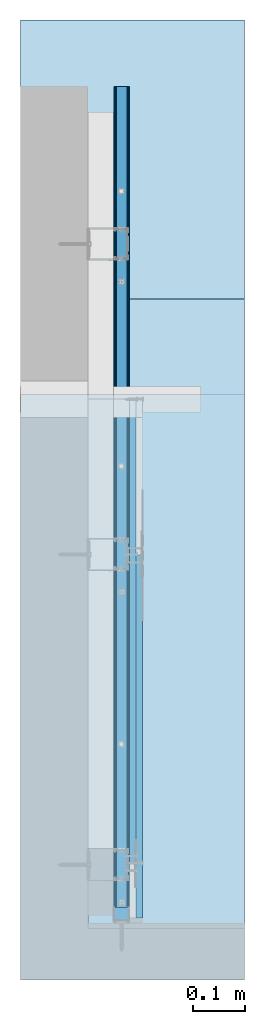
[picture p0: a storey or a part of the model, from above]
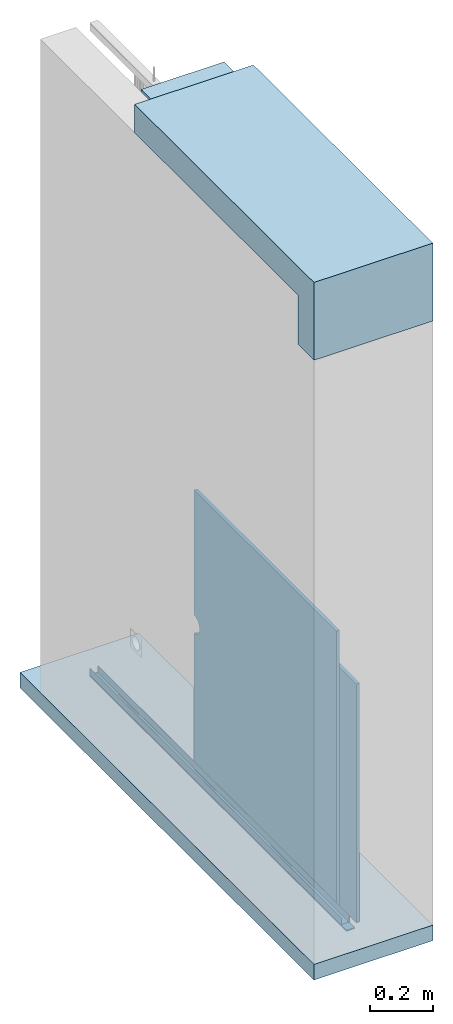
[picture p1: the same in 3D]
Properties of the parts of a building model (IFC2X3)

# File
Description: ViewDefinition [CoordinationView_V2.0]
File name: kolizja nr 5.ifc
Time: 2025-10-29T14:54:42
Written by: IFC-manager for SketchUp (5.5.4)
Made in: SketchUp 2026 (26.0.429)

# IfcSite, Default Site
Description: Description of Default Site; RefElevation: 254 mm

# IfcBuilding, Default Building
Description: Description of Default Building; ElevationOfRefHeight: 0 mm; ElevationOfTerrain: 0 mm

# IfcBuildingStorey, Default Building Storey
In: Default Building
Description: Description of Default Building Storey; Elevation: 57.6156 mm
Parametry kolizji SG - Elementkolizyjnykonstrukcyjnyinstalacyjny: Rura instalacyjna o małej średnicy; ElementsystemuSaintGobain: Okładzina ścienna; Izolacyjnoscakustyczna: niezweryfikowana; Klasaodpornosciogniowej: -; LODlevelofDevelopment: 400; Nrdetalu: 5.57.021; Opis: Detal przejścia rury o małej średnicy przez okładzinę ścienną wykonaną w systemie RIGIPS; Producent: SAINT-GOBAIN; Sposobwykonania: W przypadku koniecznoÅ›ci poprowadzenia przewodu rurowego o maÅ‚ej Å›rednicy ( Ã˜<25mm) przez okÅ‚adzinÄ™ Å›ciennÄ… w systemie RIGIPS naleÅ¼y zaprojektowaÄ‡ jego przebieg w taki sposÃ³b, aby nie kolidowaÅ‚ z profilami pionowymi CD 60. JeÅ¼eli kolizja z profilem CD 60 jest nieunikniona, naleÅ¼y przewidzieÄ‡ i wykonaÄ‡ w Å›cianie dodatkowy profil pionowy CD 60, zapewniajÄ…cy prawidÅ‚owe usztywnienie konstrukcji. W miejscu przejÅ›cia instalacji naleÅ¼y wykonaÄ‡ otwÃ³r okrÄ…gÅ‚y w pÅ‚ytach gipsowo-kartonowych o wymiarach wiÄ™kszych od Å›rednicy rury o 10â€“20 mm. PrzestrzeÅ„ pomiÄ™dzy krawÄ™dziÄ… rury a krawÄ™dziÄ… otworu naleÅ¼y wypeÅ‚niÄ‡ weÅ‚nÄ… mineralnÄ… ISOVER, a nastÄ™pnie na wypeÅ‚nienie zastosowaÄ‡ masÄ™ szpachlowÄ… RIGIPS, zapewniajÄ…c szczelne i estetyczne wykoÅ„czenie powierzchni Å›ciany.; Typkolizji: twarda; Warianty: -

# IfcSlab: Beton#1, Beton
In: Default Building Storey
Type - PredefinedType: FLOOR
Material: Concrete_02_1K
Qto_SlabBaseQuantities - NetVolume: 0.048222 m3; Depth: 59.9996 mm; NetArea: 0.803705 m2

# IfcSlab: Strop#1, Strop
In: Default Building Storey
Type - PredefinedType: FLOOR
Material: Concrete_02_1K
Qto_SlabBaseQuantities - NetVolume: 0.0590179 m3; Depth: 300 mm; NetArea: 0.196726 m2

# IfcSlab: Strop#2, Strop
In: Default Building Storey
Type - PredefinedType: FLOOR
Material: Concrete_04_1K
Qto_SlabBaseQuantities - NetVolume: 0.00426325 m3; Depth: 200 mm; NetArea: 0.0213163 m2

# IfcWall: Kołek rozporowy min. fi 6#10 (7)
In: Default Building Storey
Type - Description: Description of Object
Material: Default

# IfcWall: Kołek rozporowy min. fi 6#11, Kołek rozporowy min. fi 6
In: Default Building Storey
Type - Description: Description of Object
Material: Default

# IfcWall: Kołek rozporowy min. fi 6#12, Kołek rozporowy min. fi 6
In: Default Building Storey
Type - Description: Description of Object
Material: Default

# IfcWall: Kołek rozporowy min. fi 6#13 (9)
In: Default Building Storey
Type - Description: Description of Object
Material: Default

# IfcWall: Kołek rozporowy min. fi 6#14 (9)
In: Default Building Storey
Type - Description: Description of Object
Material: Default

# IfcWall: Kołek rozporowy min. fi 6#7 (4)
In: Default Building Storey
Type - Description: Description of Object
Material: Default

# IfcWall: Kołek rozporowy min. fi 6#8 (7)
In: Default Building Storey
Type - Description: Description of Object
Material: Default

# IfcWall: Kołek rozporowy min. fi 6#9 (4)
In: Default Building Storey
Type - Description: Description of Object
Material: Default

# IfcWall: Masa szpachlowa konstrukcyjna RIGIPS
In: Default Building Storey
Type - Description: Description of Object
Material: Undefined5
Qto_WallBaseQuantities - NetVolume: 0.0000660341 m3; Width: 3.20005 mm; Length: 91 mm; NetSideArea: 0.0206353 m2

# IfcWall: Masa szpachlowa konstrukcyjna RIGIPS#1, Masa szpachlowa konstrukcyjna RIGIPS
In: Default Building Storey
Type - Description: Description of Object
Material: Undefined5
Qto_WallBaseQuantities - NetVolume: 0.000250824 m3

# IfcWall: Masa szpachlowa konstrukcyjna RIGIPS#4, Masa szpachlowa konstrukcyjna RIGIPS
In: Default Building Storey
Type - Description: Description of Object
Material: Undefined5
Qto_WallBaseQuantities - NetVolume: 0.00011014 m3; Width: 3.20005 mm; Length: 91 mm; NetSideArea: 0.0344181 m2

# IfcWall: Masa szpachlowa konstrukcyjna RIGIPS#5, Masa szpachlowa konstrukcyjna RIGIPS
In: Default Building Storey
Type - Description: Description of Object
Material: Undefined5
Qto_WallBaseQuantities - NetVolume: 0.000628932 m3

# IfcWall: Masa szpachlowa wykończeniowa RIGIPS
In: Default Building Storey
Type - Description: Description of Object
Material: Undefined2
Qto_WallBaseQuantities - NetVolume: 0.0000477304 m3; Width: 0.959873 mm; Length: 250 mm; NetSideArea: 0.0497257 m2

# IfcWall: Profil RIGIPS CD 60 GypSerra®/Ultrastil®#3 (3)
In: Default Building Storey
Type - Description: Description of Object
Material: Default

# IfcWall: Profil RIGIPS UD 30 GypSerra®/Ultrastil®
In: Default Building Storey
Type - Description: Description of Object
Material: Undefined9
Qto_WallBaseQuantities - NetVolume: 0.0000727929 m3

# IfcWall: Profil RIGIPS UD 30 GypSerra®/Ultrastil®#1, Profil RIGIPS UD 30 GypSerra®/Ultrastil®
In: Default Building Storey
Type - Description: Description of Object
Material: Undefined9
Qto_WallBaseQuantities - NetVolume: 0.0000742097 m3

# IfcWall: Profil RIGIPS UD 30 GypSerra®/Ultrastil®#2, Profil RIGIPS UD 30 GypSerra®/Ultrastil®
In: Default Building Storey
Type - Description: Description of Object
Material: Undefined9
Qto_WallBaseQuantities - NetVolume: 0.000113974 m3

# IfcWall: Przewód instalacyjny - okrągły
In: Default Building Storey
Material: M00_Soft_Cloud
Qto_WallBaseQuantities - NetVolume: 0.0000799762 m3

# IfcWall: Płyta gipsowo-kartonowa RIGIPS PRO (4PRO™)#2, Płyta gipsowo-kartonowa RIGIPS PRO (4PRO™)
In: Default Building Storey
Type - Description: Description of Object
Material: Undefined7
Qto_WallBaseQuantities - NetVolume: 0.00134186 m3; Width: 12.5 mm; Length: 104.369 mm; NetSideArea: 0.107349 m2

# IfcWall: Płyta gipsowo-kartonowa RIGIPS PRO (4PRO™)#4, Płyta gipsowo-kartonowa RIGIPS PRO (4PRO™)
In: Default Building Storey
Type - Description: Description of Object
Material: Undefined7
Qto_WallBaseQuantities - NetVolume: 0.00800702 m3; Width: 12.5 mm; Length: 700.477 mm; NetSideArea: 0.640562 m2

# IfcWall: Płyta gipsowo-kartonowa RIGIPS PRO (4PRO™)#5, Płyta gipsowo-kartonowa RIGIPS PRO (4PRO™)
In: Default Building Storey
Type - Description: Description of Object
Material: Undefined7
Qto_WallBaseQuantities - NetVolume: 0.0118819 m3; Width: 12.5 mm; Length: 898.639 mm; NetSideArea: 0.950551 m2

# IfcWall: Płyta gipsowo-kartonowa RIGIPS PRO (4PRO™)#6, Płyta gipsowo-kartonowa RIGIPS PRO (4PRO™)
In: Default Building Storey
Type - Description: Description of Object
Material: Undefined7
Qto_WallBaseQuantities - NetVolume: 0.00340008 m3; Width: 12.5 mm; Length: 301.531 mm; NetSideArea: 0.272006 m2

# IfcWall: Taśma spoinowa RIGIPS#1, Taśma spoinowa RIGIPS
In: Default Building Storey
Type - Description: Description of Object
Material: Undefined8
Qto_WallBaseQuantities - NetVolume: 0.0000226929 m3; Width: 0.500202 mm; Length: 50 mm; NetSideArea: 0.0453675 m2

# IfcWall: Taśma uszczelniająca piankowa RIGIPS szer.30mm#1 (9)
In: Default Building Storey
Type - Description: Description of Object
Material: Default

# IfcWall: Taśma uszczelniająca piankowa RIGIPS#3 (2)
In: Default Building Storey
Type - Description: Description of Object
Material: Undefined13
Qto_WallBaseQuantities - NetVolume: 0.000145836 m3

# IfcWall: Taśma uszczelniająca piankowa RIGIPS#4, Taśma uszczelniająca piankowa RIGIPS
In: Default Building Storey
Type - Description: Description of Object
Material: Undefined13
Qto_WallBaseQuantities - NetVolume: 0.00022365 m3

# IfcWall: Uchwyt Rigips ES do profili CD60 (9)
In: Default Building Storey
Type - Description: Description of Object
Name | Material
3 x Uchwyt Rigips ES do profili CD60 | Default
6 x Uchwyt Rigips ES do profili CD60 | Undefined3

# IfcWall: Uszczelnienie wełną mineralną ISOVER#1, Uszczelnienie wełną mineralną ISOVER
In: Default Building Storey
Material: D02_Buttercup_Glow

# IfcWall: Wkręt RIGIPS "pchełka" 3,9x11mm#1 (9)
In: Default Building Storey
Type - Description: Description of Object
Name | Material
3 x Wkręt RIGIPS "pchełka" 3,9x11mm | Default
6 x Wkręt RIGIPS "pchełka" 3,9x11mm | Undefined4

# IfcWall: Wkręt RIGIPS "pchełka" 3,9x11mm#2 (9)
In: Default Building Storey
Type - Description: Description of Object
Name | Material
3 x Wkręt RIGIPS "pchełka" 3,9x11mm | Default
6 x Wkręt RIGIPS "pchełka" 3,9x11mm | Undefined4

# IfcWall: Wkręt RIGIPS "pchełka" 3,9x11mm#3 (9)
In: Default Building Storey
Type - Description: Description of Object
Name | Material
3 x Wkręt RIGIPS "pchełka" 3,9x11mm | Default
6 x Wkręt RIGIPS "pchełka" 3,9x11mm | Undefined4

# IfcWall: Wkręt RIGIPS "pchełka" 3,9x11mm#4 (9)
In: Default Building Storey
Type - Description: Description of Object
Material: Undefined4

# IfcWall: Wkręt RIGIPS TN 25#11 (4)
In: Default Building Storey
Type - Description: Description of Object
Material: Default

# IfcWall: Wkręt RIGIPS TN 25#7 (2)
In: Default Building Storey
Type - Description: Description of Object
Material: Undefined6

# IfcWall: Wkręt RIGIPS TN 25#8 (2)
In: Default Building Storey
Type - Description: Description of Object
Material: Undefined6

# IfcWall: Wkręt RIGIPS TN 35#10 (2)
In: Default Building Storey
Type - Description: Description of Object
Material: Undefined6

# IfcWall: Wkręt RIGIPS TN 35#11 (2)
In: Default Building Storey
Type - Description: Description of Object
Material: Undefined6

# IfcWall: Wkręt RIGIPS TN 35#13, Wkręt RIGIPS TN 35
In: Default Building Storey
Type - Description: Description of Object
Material: Undefined6

# IfcWall: Wkręt RIGIPS TN 35#14, Wkręt RIGIPS TN 35
In: Default Building Storey
Type - Description: Description of Object
Material: Undefined6

# IfcWall: Wkręt RIGIPS TN 35#15 (2)
In: Default Building Storey
Type - Description: Description of Object
Material: Undefined6

# IfcWall: Wkręt RIGIPS TN 35#16, Wkręt RIGIPS TN 35
In: Default Building Storey
Type - Description: Description of Object
Material: Undefined6

# IfcWall: Wkręt RIGIPS TN 35#17, Wkręt RIGIPS TN 35
In: Default Building Storey
Type - Description: Description of Object
Material: Undefined6

# IfcWall: Wkręt RIGIPS TN 35#18 (2)
In: Default Building Storey
Type - Description: Description of Object
Material: Undefined6

# IfcWall: Wkręt RIGIPS TN 35#19, Wkręt RIGIPS TN 35
In: Default Building Storey
Type - Description: Description of Object
Material: Undefined6

# IfcWall: Wkręt RIGIPS TN 35#20, Wkręt RIGIPS TN 35
In: Default Building Storey
Type - Description: Description of Object
Material: Undefined6

# IfcWall: Wkręt RIGIPS TN 35#21 (2)
In: Default Building Storey
Type - Description: Description of Object
Material: Undefined6

# IfcWall: Wypełnienie masą szpachlową RIGIPS (2)
In: Default Building Storey
Material: M08_Obsidian_Black
Qto_WallBaseQuantities - NetVolume: 0.0000119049 m3; Width: 12.5 mm; Length: 35 mm; NetSideArea: 0.000952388 m2

# IfcWall: Wypełnienie z wełny mineralnej szklanej ISOVER#1, Wypełnienie z wełny mineralnej szklanej ISOVER
In: Default Building Storey
Type - Description: Description of Object
Material: Undefined
Qto_WallBaseQuantities - NetVolume: 0.00451831 m3; Width: 50 mm; Length: 224.108 mm; NetSideArea: 0.0903662 m2

# IfcWall: Wypełnienie z wełny mineralnej szklanej ISOVER#12 (2)
In: Default Building Storey
Type - Description: Description of Object
Material: Default

# IfcWall: Wypełnienie z wełny mineralnej szklanej ISOVER#13, Wypełnienie z wełny mineralnej szklanej ISOVER
In: Default Building Storey
Type - Description: Description of Object
Material: Undefined
Qto_WallBaseQuantities - NetVolume: 0.00116331 m3; Width: 49.9999 mm; Length: 57.7 mm; NetSideArea: 0.0232661 m2

# IfcWall: Wypełnienie z wełny mineralnej szklanej ISOVER#14, Wypełnienie z wełny mineralnej szklanej ISOVER
In: Default Building Storey
Type - Description: Description of Object
Material: Undefined
Qto_WallBaseQuantities - NetVolume: 0.00285645 m3; Width: 49.9999 mm; Length: 67.8781 mm; NetSideArea: 0.0571291 m2

# IfcWall: Wypełnienie z wełny mineralnej szklanej ISOVER#15, Wypełnienie z wełny mineralnej szklanej ISOVER
In: Default Building Storey
Type - Description: Description of Object
Material: Undefined
Qto_WallBaseQuantities - NetVolume: 0.022576 m3; Width: 49.9999 mm; Length: 538 mm; NetSideArea: 0.451522 m2

# IfcWall: Wypełnienie z wełny mineralnej szklanej ISOVER#16, Wypełnienie z wełny mineralnej szklanej ISOVER
In: Default Building Storey
Type - Description: Description of Object
Material: Undefined
Qto_WallBaseQuantities - NetVolume: 0.0165885 m3; Width: 49.9999 mm; Length: 538 mm; NetSideArea: 0.33177 m2

# IfcWall: Wypełnienie z wełny mineralnej szklanej ISOVER#17, Wypełnienie z wełny mineralnej szklanej ISOVER
In: Default Building Storey
Type - Description: Description of Object
Material: Default

# IfcWall: Wypełnienie z wełny mineralnej szklanej ISOVER#18, Wypełnienie z wełny mineralnej szklanej ISOVER
In: Default Building Storey
Type - Description: Description of Object
Material: Default

# IfcWall: Wypełnienie z wełny mineralnej szklanej ISOVER#19, Wypełnienie z wełny mineralnej szklanej ISOVER
In: Default Building Storey
Type - Description: Description of Object
Material: Default

# IfcWall: Wypełnienie z wełny mineralnej szklanej ISOVER#20, Wypełnienie z wełny mineralnej szklanej ISOVER
In: Default Building Storey
Type - Description: Description of Object
Material: Undefined
Qto_WallBaseQuantities - NetVolume: 0.00253742 m3; Width: 49.9999 mm; Length: 67.8781 mm; NetSideArea: 0.0507486 m2

# IfcWall: Wypełnienie z wełny mineralnej szklanej ISOVER#21, Wypełnienie z wełny mineralnej szklanej ISOVER
In: Default Building Storey
Type - Description: Description of Object
Material: Undefined
Qto_WallBaseQuantities - NetVolume: 0.0242976 m3; Width: 49.9999 mm; Length: 538 mm; NetSideArea: 0.485954 m2

# IfcWall: Wypełnienie z wełny mineralnej szklanej ISOVER#8, Wypełnienie z wełny mineralnej szklanej ISOVER
In: Default Building Storey
Type - Description: Description of Object
Material: Undefined
Qto_WallBaseQuantities - NetVolume: 0.00306557 m3; Width: 49.9999 mm; Length: 67.8781 mm; NetSideArea: 0.0613115 m2

# IfcWall: Wypełnienie z wełny mineralnej szklanej ISOVER#9, Wypełnienie z wełny mineralnej szklanej ISOVER
In: Default Building Storey
Type - Description: Description of Object
Material: Undefined
Qto_WallBaseQuantities - NetVolume: 0.0121488 m3; Width: 49.9999 mm; Length: 269 mm; NetSideArea: 0.242977 m2

# IfcWall: Ściana#1, Ściana
In: Default Building Storey
Material: M04_Stone_Frost
Qto_WallBaseQuantities - NetVolume: 0.00705387 m3

# IfcWall: Ściana#2, Ściana
In: Default Building Storey
Material: M03_Pewter_Shine
Qto_WallBaseQuantities - NetVolume: 0.633084 m3; Width: 433 mm; Length: 2518.01 mm; NetSideArea: 1.46209 m2
